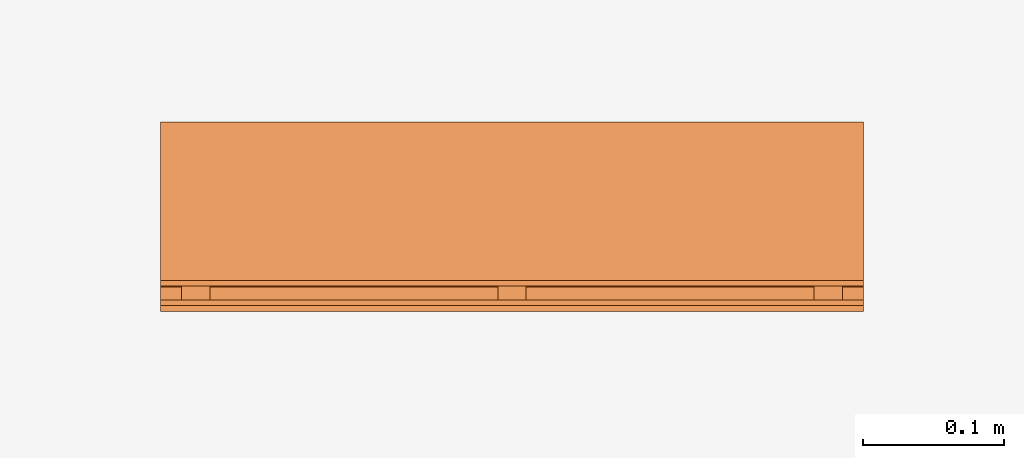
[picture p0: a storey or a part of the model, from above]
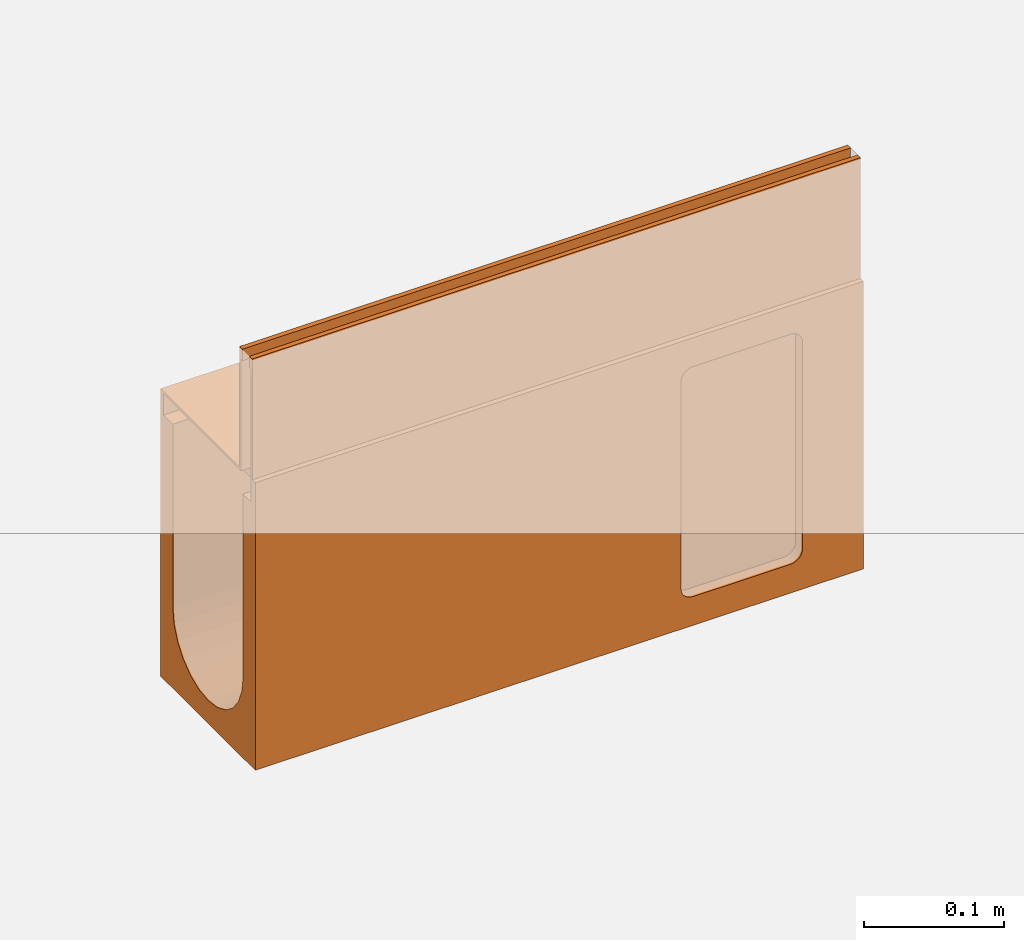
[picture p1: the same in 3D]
Properties of the parts of a building model (IFC2X3)

# File
Description: ViewDefinition [CoordinationView]
File name: 23201 - No 20.1J Constant Depth Channel - 500mm LG - Invert Depth 230mm.ifc
Time: 2013-10-31T17:33:51
Written by: Autodesk Revit 2013
Made in: 20120221_2030(x64)

# IfcProject, Project Number
LongName: Project Name; Phase: Project Status

# IfcSite, Default
RefLatitude: 42, 21, 30, 344238; RefLongitude: -71, -3, -35, -194702; RefElevation: 0 mm

# IfcBuilding
Pset_BuildingCommon - NumberOfStoreys: 1
Other - Client Name: Owner; Project Number: Project Number; Project Name: Project Name; Project Address: ## Street City, State Zip; Project Status: Project Status; Project Issue Date: Issue Date

# IfcBuildingStorey, Level 1
LongName: Level 1; Elevation: 0 mm
Constraints - Elevation Base: 0; Elevation: 0 mm
Graphics - Symbol at End 1 Default: no; Line Pattern: Center; Symbol: M_Level Head - Circle: M_Level Head - Circle; Line Weight: 1; Color: 0; Symbol at End 2 Default: yes
Identity Data - Name: Level 1; Building Story: yes; Structural: no
Dimensions - Computation Height: 0 mm

# IfcBuildingElementProxy: 23201 - No 20.1J Constant Depth Channel - 500mm LG - Invert Depth 230mm, Civil-Drainage-Channel-ACO-MultiDrain-M100D-Brickslot-Channel-System:23201 - No 20.1J Constant Depth Channel - 500mm LG - Invert Depth 230mm:23201 - No 20.1J Constant Depth Channel - 500mm LG - Invert Depth 230mm:196059
In: Level 1
Material: Steel, Galvanized, Vienite® Synthetic Resin Concrete
Phasing - Phase Created: New Construction
Dimensions - FloorCut_Length: -500 mm; Brickslot Access Unit Void Depth: -6500 mm; Length: 1000 mm; Brickslot Void Depth: 0 mm; EndCap Position: 500 mm; Custom_Void_length: 500 mm; Brickslot Access Unit Void Bottom Depth: -6605 mm; Brickslot Void Length: 500 mm; Volume: 5559205 mm3; SlopingEndOverallDepth: 250 mm; SlopingInvertDepth: 175 mm; FloorCut_Depth: 250 mm; ShallowOverallDepth: 75 mm; Access_Custom_Void_Length: 0 mm; Depth: 250 mm; Brickslot Access Unit Floor Cut Length: 500 mm; FloorCut_Width: 135 mm; InvDepth: 180 mm; EndCap_Height: 250 mm; SlopingEndInvertDepth: 180 mm; GratingLength: -1000 mm; Floor Cut Gap: 105 mm; ShallowInvDepth: 55 mm; SlopingOverallDepth: 245 mm; Length Drain: -500 mm
Construction - 23466_Load Class D400_Brickslot Grating_Galvanized Steel_500mm Long: yes; 23465_Load Class D400_Brickslot Grating_Galvanized Steel_1000mm Long: no; 23462_Load Class C250_Brickslot Access Unit_Galvanised Steel_500mm Long: no; 23404_Universal Endcap (Male End): no; 23461_Load Class C250_Brickslot Grating_Galvanized Steel_500mm Long: no; 23404_Universal Endcap (Female End): no; 23467_Load Class D400_Brickslot Access Unit_Galvanised Steel_500mm Long: no; 23460_Load Class C250_Brickslot Grating_Galvanized Steel_1000mm Long: no; Constant Depth Junction Channel: yes; Shallow Depth Channel with seal: no; 23410_Sump Unit: no; Constant Depth Channel: no; Sloping Channel: no; Shallow Depth Channel: no
Constraints - Moves With Nearby Elements: no; Level: Level: Level 1
Pset_BuildingElementProxyCommon - Reference: 23201 - No 20.1J Constant Depth Channel - 500mm LG - Invert Depth 230mm
General - SerialNumber: 0; TagNumber: 0
Data - Pre-formed Outlet Ø: N/A; Product Standard: BS EN 1433:2002, CE marked; Hydraulic Performance: http://www.aco.co.uk/download.php?id=173; Product Dimensions: 500mm x 135mm x 250mm (LxWxH); Load Class: A 15 - D 400; Concrete Surround Volume - Load Class B 125 - C 250 - Concrete Pavement: 0.14m³/m; Product Weight: 10.8 Kg; Installation - Concrete Grade: Refer to brochure; Invert Depth: 230mm; Concrete Surround Volume - Load Class D 400 - Concrete Pavement: 0.21m³/m; Channel C.S.A: 0.017m²; Concrete Surround Volume - Load Class A 15 - Concrete Pavement: 0.09m³/m; ACO Hydraulic Design Software: http://www.acodesign.co.uk
Materials and Finishes - Edge Rail Finish: Pre-galvanised; Channel Colour: Brown; Edge Rail Colour: Silver; Edge Rail Material: Steel; Channel Material: Vienite® Synthetic Resin Concrete
Model Properties - Brickslot Access Unit Product code 23462: Load Class C250 - Brickslot Access Unit Galvanised Steel - 500mm long x 105mm high - 10mm Slot - Intake area - 10000mm²/m - 6.4 Kg; Brickslot Grating Product code 23460: N/A; Brickslot Access Unit Product code 23467: Load Class D400 - Brickslot Access Unit Galvanised Steel - 500mm long x 105mm high - 10mm Slot - Intake area - 10000mm²/m - 6.4 Kg; Brickslot Grating Product code 23461: Load Class C250 - Brickslot Galvanised Steel - 500mm long x 105mm high - 10mm Slot - Intake area - 10000mm²/m -3.3 Kg; End Cap Product code 23404: No 306 Universal End Cap - 135mm wide x 300mm long - Spigot Ø110mm x 50mm long - Silver - Polypropylene - 0.16kg; Brickslot Grating Product code 23466: Load Class D400 - Brickslot Galvanised Steel - 500mm long x 105mm high - 10mm Slot - Intake area - 10000mm²/m - 3.3 Kg; Brickslot Grating Product code 23465: N/A
Identity Data - Product Code: 23201; Type Comments: ACO MultiDrain M100D 20.1J Constant Depth Junction Channel 500mm Long; e-mail Technical: technical@aco.co.uk; e-mail Sales: customersupport@aco.co.uk; Installation guidelines: http://www.aco.co.uk/download.php?id=173; Product brochure: http://www.aco.co.uk/download.php?id=173; Price: POA - contact ACO; Telephone: +44 (0)1462 816666; Assembly Code: D2040; Product Page URL: http://www.aco.co.uk/product_detail.php?id=58; Watermark 1: This file is the property of ACO Technologies PLC; Cost: 0; OmniClass Title: Rainwater Removal; Watermarked With: BIM Manager Premium Suite; OmniClass Number: 23.70.50.24; URL: www.aco.co.uk; Assembly Description: Rain Water Drainage; Maintenance guidelines: http://www.aco.co.uk/download.php?id=173; Watermark 2: This file is water marked and users are prohibited to reproduce, adapt, distribute this information; Model: ACO MultiDrain MD Brickslot- M100D; Fax: +44 (0)1462 815895; Address: ACO Business Park, Hitchin Road, Shefford, Bedfordshire, United Kingdom SG17 5TE; Manufacturer: ACO Technologies plc - ACO Water Management Division; Model Description: Channel drainage system
Green Building Properties - Edge Rail Recycled Material Content: Between 40% - 90%; Edge Rail Recyclable: Fully recyclable; Channel Recycled Material Content: 20% minimum; Channel Recyclable: Fully recyclable
Other - Revision: 1; Created By: www.aco.co.uk; Watermarked By: www.aco.co.uk

# IfcOpeningElement: Recess (2)
In: Level 1
Dimensions - Thickness: 1000 mm; Volume: 24982180000 mm3; Perimeter: 20000 mm; Area: 25000000 mm2
Constraints - Room Bounding: yes; Related to Mass: no; Height Offset From Level: 0 mm; Level: Level: Level 1
Phasing - Phase Created: New Construction
Structural - Enable Analytical Model: no; Structural: no
Materials and Finishes - Structural Material: Earth
Analytical Properties - Thermal Resistance (R): 1.19474; Absorptance: 0.1; Roughness: 1; Thermal mass: 1359800; Heat Transfer Coefficient (U): 0.837
Graphics - Coarse Scale Fill Color: 0
Construction - Function: 0; Default Thickness: 1000 mm

# IfcSlab: Floor:Generic Floor - 1000mm, Floor:Generic Floor - 1000mm:193825
In: Level 1
PredefinedType: FLOOR; Material: Earth 1000 mm
Dimensions - Thickness: 1000 mm; Volume: 24982180000 mm3; Perimeter: 20000 mm; Area: 25000000 mm2
Constraints - Room Bounding: yes; Related to Mass: no; Height Offset From Level: 0 mm; Level: Level: Level 1
Phasing - Phase Created: New Construction
Structural - Enable Analytical Model: no; Structural: no
Pset_SlabCommon - Reference: Generic Floor - 1000mm; IsExternal: no; LoadBearing: yes
Materials and Finishes - Structural Material: Earth
Analytical Properties - Thermal Resistance (R): 1.19474; Absorptance: 0.1; Roughness: 1; Thermal mass: 1359800; Heat Transfer Coefficient (U): 0.837
Graphics - Coarse Scale Fill Color: 0
Construction - Function: 0; Default Thickness: 1000 mm
